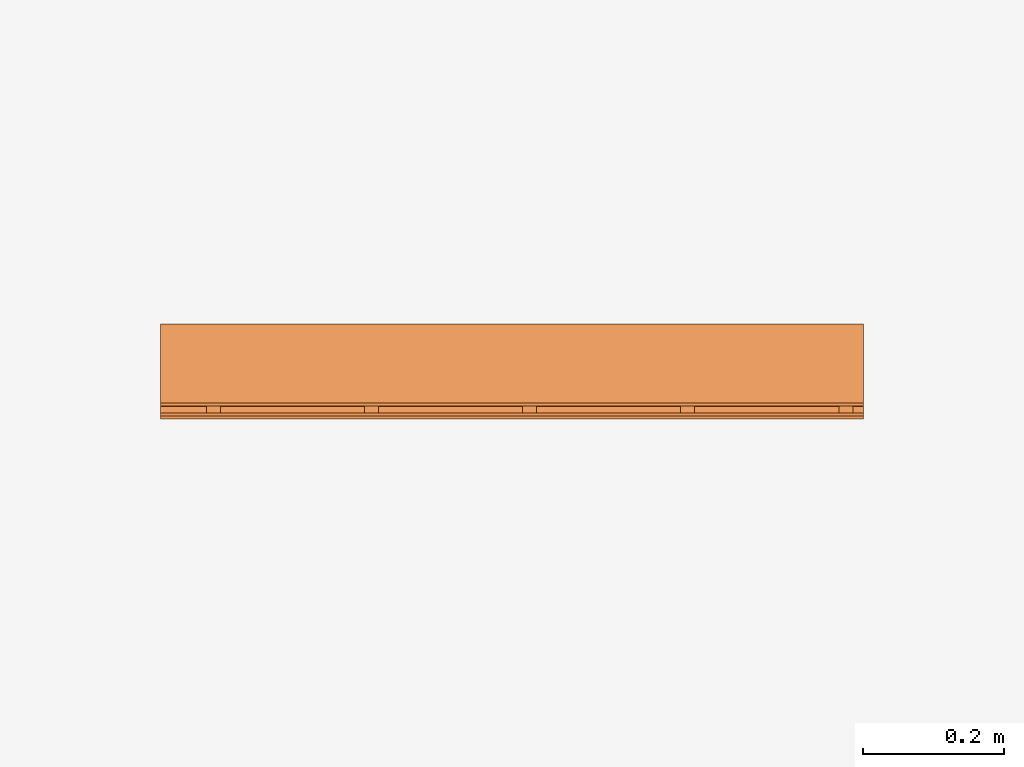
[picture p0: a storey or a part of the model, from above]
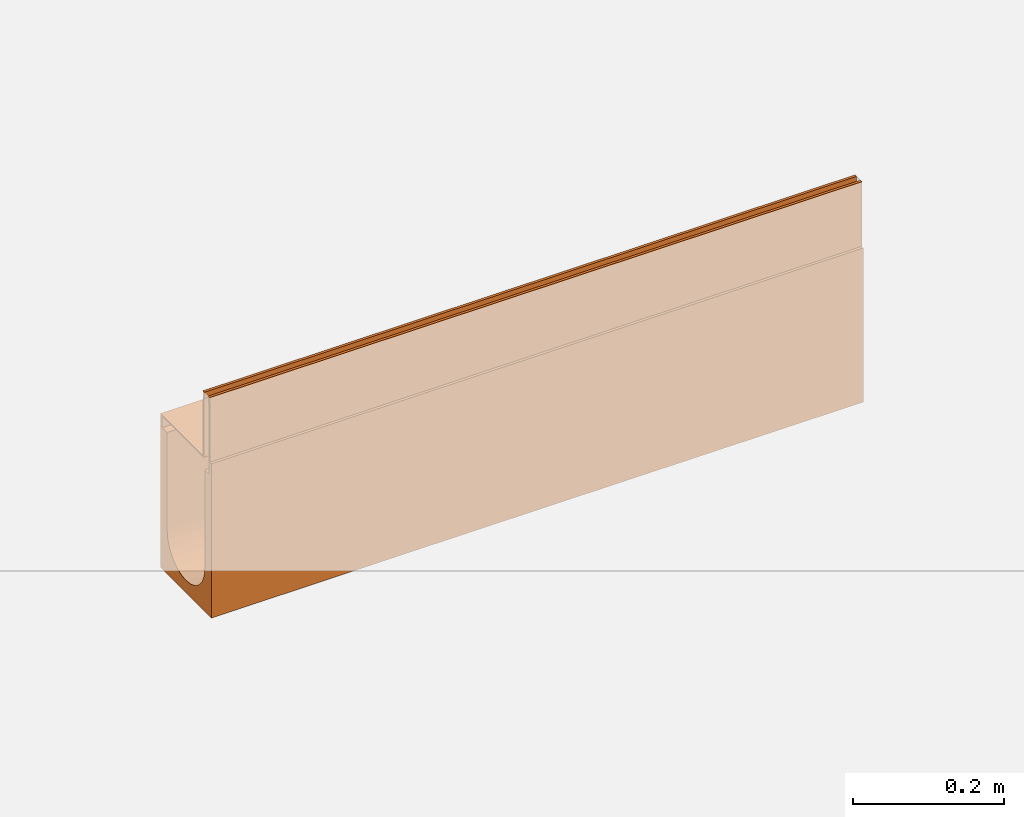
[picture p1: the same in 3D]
Properties of the parts of a building model (IFC2X3)

# File
Description: ViewDefinition [CoordinationView]
File name: 23200 - No 20.0 Constant Depth Channel - 1000mm LG - Invert Depth 230mm.ifc
Time: 2013-10-31T17:33:30
Written by: Autodesk Revit 2013
Made in: 20120221_2030(x64)

# IfcProject, Project Number
LongName: Project Name; Phase: Project Status

# IfcSite, Default
RefLatitude: 42, 21, 30, 344238; RefLongitude: -71, -3, -35, -194702; RefElevation: 0 mm

# IfcBuilding
Pset_BuildingCommon - NumberOfStoreys: 1
Other - Project Address: ## Street City, State Zip; Project Number: Project Number; Project Issue Date: Issue Date; Project Name: Project Name; Client Name: Owner; Project Status: Project Status

# IfcBuildingStorey, Level 1
LongName: Level 1; Elevation: 0 mm
Constraints - Elevation Base: 0; Elevation: 0 mm
Graphics - Line Weight: 1; Color: 0; Symbol: M_Level Head - Circle: M_Level Head - Circle; Symbol at End 1 Default: no; Symbol at End 2 Default: yes; Line Pattern: Center
Identity Data - Structural: no; Building Story: yes; Name: Level 1
Dimensions - Computation Height: 0 mm

# IfcBuildingElementProxy: 23200 - No 20.0 Constant Depth Channel - 1000mm LG - Invert Depth 230mm, Civil-Drainage-Channel-ACO-MultiDrain-M100D-Brickslot-Channel-System:23200 - No 20.0 Constant Depth Channel - 1000mm LG - Invert Depth 230mm:23200 - No 20.0 Constant Depth Channel - 1000mm LG - Invert Depth 230mm:196059
In: Level 1
Material: Steel, Galvanized, Vienite® Synthetic Resin Concrete
Construction - 23467_Load Class D400_Brickslot Access Unit_Galvanised Steel_500mm Long: no; 23404_Universal Endcap (Female End): no; 23465_Load Class D400_Brickslot Grating_Galvanized Steel_1000mm Long: yes; 23466_Load Class D400_Brickslot Grating_Galvanized Steel_500mm Long: no; 23461_Load Class C250_Brickslot Grating_Galvanized Steel_500mm Long: no; 23404_Universal Endcap (Male End): no; 23460_Load Class C250_Brickslot Grating_Galvanized Steel_1000mm Long: no; 23462_Load Class C250_Brickslot Access Unit_Galvanised Steel_500mm Long: no; 23410_Sump Unit: no; Constant Depth Junction Channel: no; Shallow Depth Channel: no; Constant Depth Channel: yes; Shallow Depth Channel with seal: no; Sloping Channel: no
Dimensions - Brickslot Void Length: 1000 mm; Brickslot Access Unit Void Depth: -6500 mm; Volume: 11992822 mm3; Custom_Void_length: 0 mm; Length: 1000 mm; Brickslot Void Depth: 0 mm; Brickslot Access Unit Void Bottom Depth: -6605 mm; FloorCut_Length: -1000 mm; EndCap Position: 1000 mm; SlopingOverallDepth: 245 mm; SlopingInvertDepth: 175 mm; InvDepth: 180 mm; Access_Custom_Void_Length: 0 mm; Floor Cut Gap: 105 mm; SlopingEndInvertDepth: 180 mm; SlopingEndOverallDepth: 250 mm; FloorCut_Depth: 250 mm; Depth: 250 mm; EndCap_Height: 250 mm; Length Drain: -1000 mm; Brickslot Access Unit Floor Cut Length: 500 mm; FloorCut_Width: 135 mm; ShallowInvDepth: 55 mm; GratingLength: -1000 mm; ShallowOverallDepth: 75 mm
Constraints - Level: Level: Level 1; Moves With Nearby Elements: no
Phasing - Phase Created: New Construction
Pset_BuildingElementProxyCommon - Reference: 23200 - No 20.0 Constant Depth Channel - 1000mm LG - Invert Depth 230mm
Identity Data - Product Code: 23200; Watermark 1: This file is the property of ACO Technologies PLC; Maintenance guidelines: http://www.aco.co.uk/download.php?id=173; Price: POA - contact ACO; Watermark 2: This file is water marked and users are prohibited to reproduce, adapt, distribute this information; Address: ACO Business Park, Hitchin Road, Shefford, Bedfordshire, United Kingdom SG17 5TE; Type Comments: ACO MultiDrain M100D 20.0 Constant Depth Channel 1000mm Long; e-mail Sales: customersupport@aco.co.uk; Product brochure: http://www.aco.co.uk/download.php?id=173; Assembly Description: Rain Water Drainage; OmniClass Title: Rainwater Removal; Manufacturer: ACO Technologies plc - ACO Water Management Division; Telephone: +44 (0)1462 816666; Installation guidelines: http://www.aco.co.uk/download.php?id=173; Watermarked With: BIM Manager Premium Suite; URL: www.aco.co.uk; Model: ACO MultiDrain MD Brickslot- M100D; Product Page URL: http://www.aco.co.uk/product_detail.php?id=58; Fax: +44 (0)1462 815895; e-mail Technical: technical@aco.co.uk; Cost: 0; Model Description: Channel drainage system; Assembly Code: D2040; OmniClass Number: 23.70.50.24
General - SerialNumber: 0; TagNumber: 0
Data - Product Standard: BS EN 1433:2002, CE marked; Load Class: A 15 - D 400; Installation - Concrete Grade: Refer to brochure; Pre-formed Outlet Ø: N/A; Concrete Surround Volume - Load Class A 15 - Concrete Pavement: 0.09m³/m; Product Dimensions: 1000mm x 135mm x 250mm (LxWxH); Concrete Surround Volume - Load Class D 400 - Concrete Pavement: 0.21m³/m; Hydraulic Performance: http://www.aco.co.uk/download.php?id=173; Concrete Surround Volume - Load Class B 125 - C 250 - Concrete Pavement: 0.14m³/m; Channel C.S.A: 0.017m²; Invert Depth: 230mm; Product Weight: 19.3 Kg; ACO Hydraulic Design Software: http://www.acodesign.co.uk
Green Building Properties - Channel Recyclable: Fully recyclable; Edge Rail Recyclable: Fully recyclable; Edge Rail Recycled Material Content: Between 40% - 90%; Channel Recycled Material Content: 20% minimum
Materials and Finishes - Channel Colour: Brown; Edge Rail Material: Steel; Edge Rail Finish: Pre-galvanised; Edge Rail Colour: Silver; Channel Material: Vienite® Synthetic Resin Concrete
Model Properties - End Cap Product code 23404: No 306 Universal End Cap - 135mm wide x 300mm long - Spigot Ø110mm x 50mm long - Silver - Polypropylene - 0.16kg; Brickslot Grating Product code 23465: Load Class D400 - Brickslot Galvanised Steel - 1000mm long x 105mm high - 10mm Slot - Intake area - 10000mm²/m - 6.6 Kg; Brickslot Access Unit Product code 23462: Load Class C250 - Brickslot Access Unit Galvanised Steel - 500mm long x 105mm high - 10mm Slot - Intake area - 10000mm²/m - 6.4 Kg; Brickslot Grating Product code 23461: Load Class C250 - Brickslot Galvanised Steel - 500mm long x 105mm high - 10mm Slot - Intake area - 10000mm²/m -3.3 Kg; Brickslot Access Unit Product code 23467: Load Class D400 - Brickslot Access Unit Galvanised Steel - 500mm long x 105mm high - 10mm Slot - Intake area - 10000mm²/m - 6.4 Kg; Brickslot Grating Product code 23466: Load Class D400 - Brickslot Galvanised Steel - 500mm long x 105mm high - 10mm Slot - Intake area - 10000mm²/m - 3.3 Kg; Brickslot Grating Product code 23460: Load Class C250 - Brickslot Galvanised Steel - 1000mm long x 105mm high - 10mm Slot - Intake area - 10000mm²/m - 6.6 Kg
Other - Watermarked By: www.aco.co.uk; Revision: 1; Created By: www.aco.co.uk

# IfcOpeningElement: Recess (2)
In: Level 1
Constraints - Related to Mass: no; Room Bounding: yes; Level: Level: Level 1; Height Offset From Level: 0 mm
Dimensions - Perimeter: 20000 mm; Thickness: 1000 mm; Volume: 24964360000 mm3; Area: 25000000 mm2
Structural - Enable Analytical Model: no; Structural: no
Phasing - Phase Created: New Construction
Construction - Function: 0; Default Thickness: 1000 mm
Analytical Properties - Thermal Resistance (R): 1.19474; Thermal mass: 1359800; Absorptance: 0.1; Heat Transfer Coefficient (U): 0.837; Roughness: 1
Graphics - Coarse Scale Fill Color: 0
Materials and Finishes - Structural Material: Earth

# IfcSlab: Floor:Generic Floor - 1000mm, Floor:Generic Floor - 1000mm:193825
In: Level 1
PredefinedType: FLOOR; Material: Earth 1000 mm
Constraints - Related to Mass: no; Room Bounding: yes; Level: Level: Level 1; Height Offset From Level: 0 mm
Dimensions - Perimeter: 20000 mm; Thickness: 1000 mm; Volume: 24964360000 mm3; Area: 25000000 mm2
Structural - Enable Analytical Model: no; Structural: no
Phasing - Phase Created: New Construction
Pset_SlabCommon - Reference: Generic Floor - 1000mm; IsExternal: no; LoadBearing: yes
Construction - Function: 0; Default Thickness: 1000 mm
Analytical Properties - Thermal Resistance (R): 1.19474; Thermal mass: 1359800; Absorptance: 0.1; Heat Transfer Coefficient (U): 0.837; Roughness: 1
Graphics - Coarse Scale Fill Color: 0
Materials and Finishes - Structural Material: Earth
